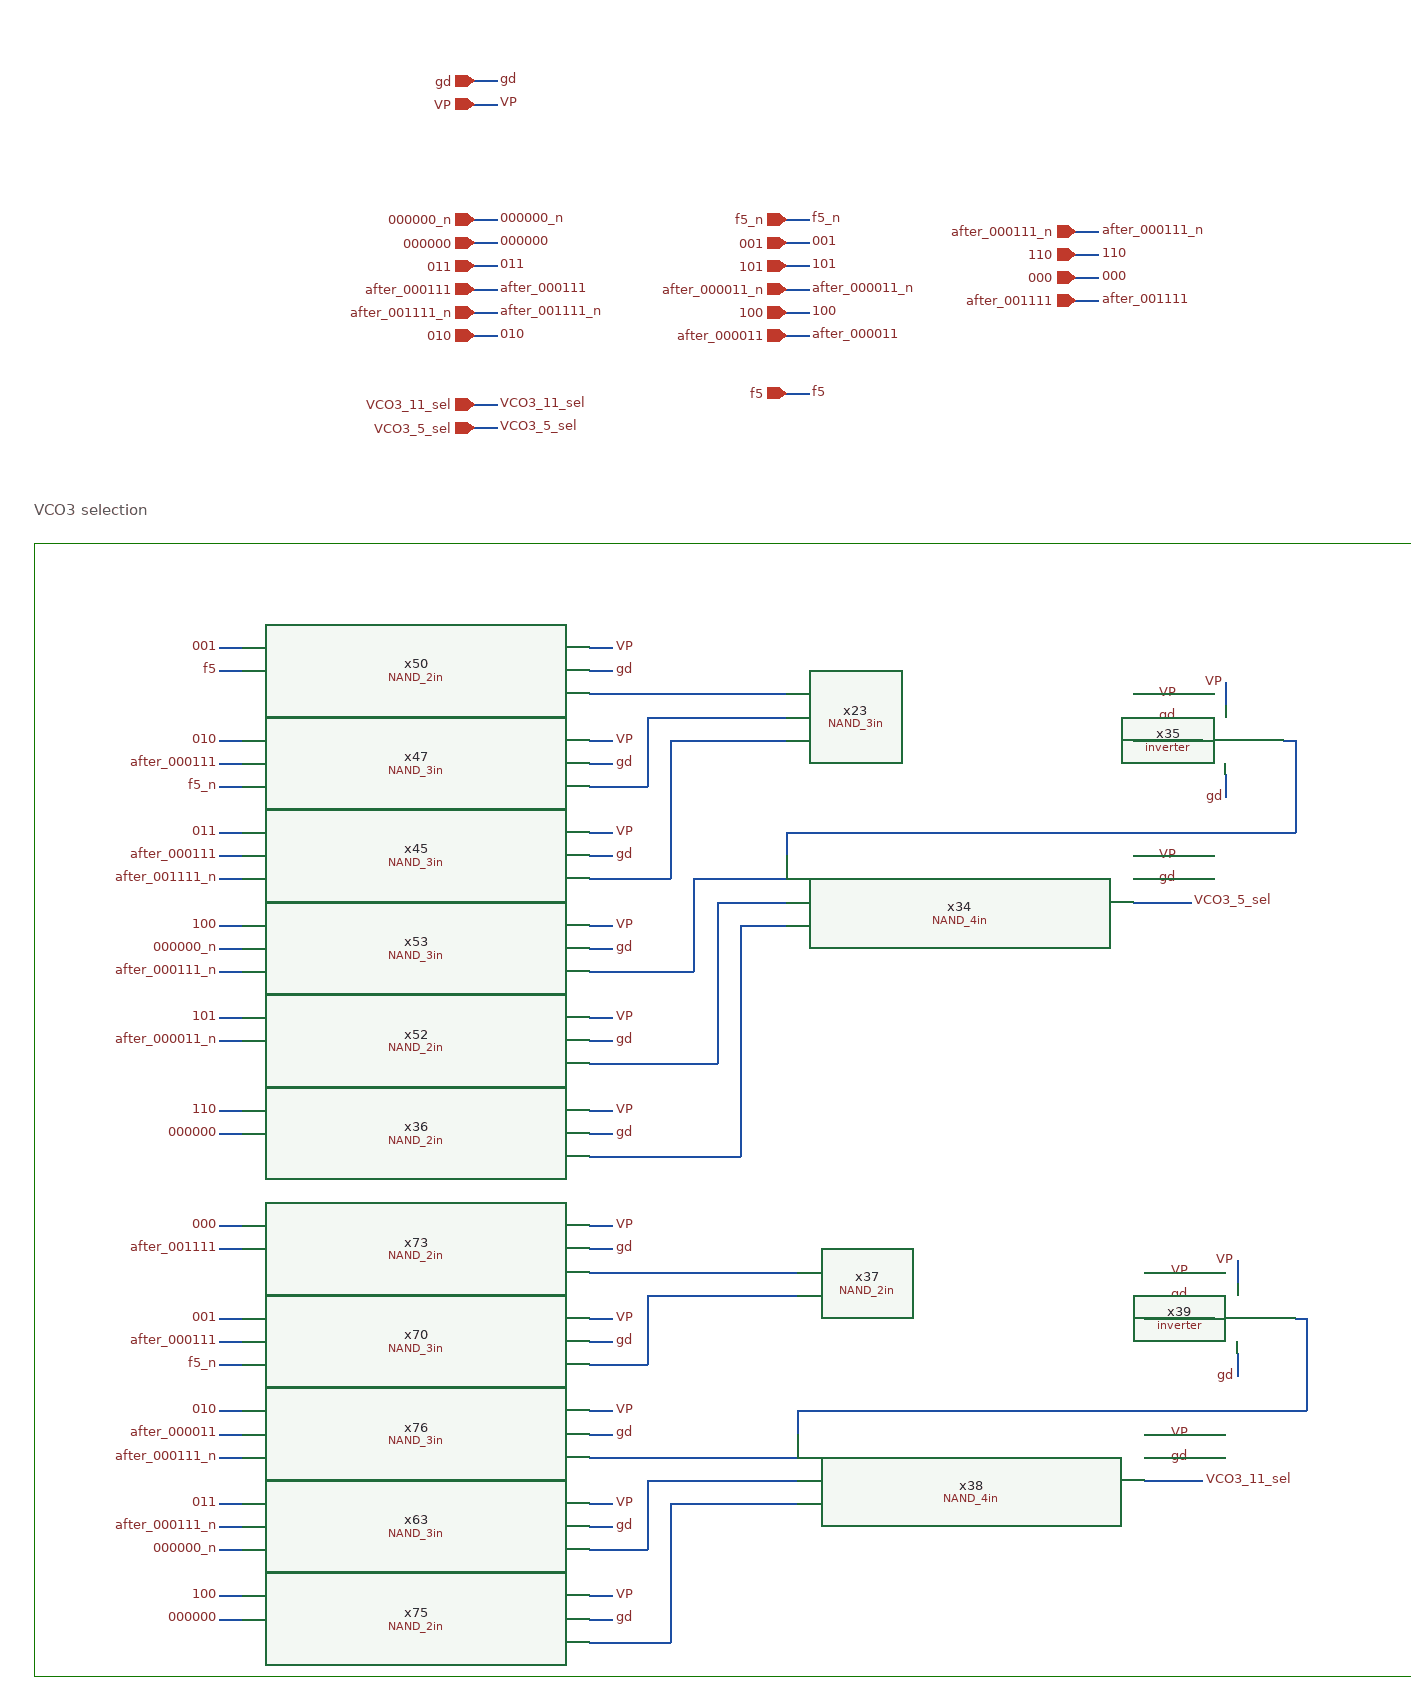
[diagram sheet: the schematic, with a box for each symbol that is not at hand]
v {xschem version=3.4.8RC file_version=1.3}
G {}
K {}
V {}
S {}
F {}
E {}
L 4 1290 -1980 1290 -1640 {}
L 4 1290 -2320 1290 -1980 {}
L 4 1290 -2520 1290 -2180 {}
L 4 1290 -2050 1290 -1710 {}
L 4 2850 -2270 2850 -1930 {}
L 4 2850 -2520 2850 -2180 {}
L 4 2850 -2050 2850 -1710 {}
L 4 1290 -2520 1630 -2520 {}
L 4 1630 -2520 1970 -2520 {}
L 4 1960 -2520 2300 -2520 {}
L 4 2180 -2520 2520 -2520 {}
L 4 1620 -2520 1960 -2520 {}
L 4 1960 -2520 2300 -2520 {}
L 4 2290 -2520 2630 -2520 {}
L 4 2510 -2520 2850 -2520 {}
L 4 1290 -1540 1630 -1540 {}
L 4 1620 -1540 1960 -1540 {}
L 4 1960 -1540 2300 -1540 {}
L 4 2290 -1540 2630 -1540 {}
L 4 2510 -1540 2850 -1540 {}
L 4 1290 -1880 1290 -1540 {}
L 4 2850 -1880 2850 -1540 {}
T {VCO3 selection} 1290 -2560 0 0 0.4 0.4 {}
N 1670 -2920 1690 -2920 {lab=gd}
N 1670 -2900 1690 -2900 {lab=VP}
N 1670 -2800 1690 -2800 {lab=000000_n}
N 1670 -2780 1690 -2780 {lab=000000}
N 1670 -2640 1690 -2640 {lab=VCO3_11_sel}
N 1670 -2620 1690 -2620 {lab=VCO3_5_sel}
N 1670 -2760 1690 -2760 {lab=011}
N 1670 -2740 1690 -2740 {lab=after_000111}
N 1670 -2720 1690 -2720 {lab=after_001111_n}
N 1670 -2700 1690 -2700 {lab=010}
N 1940 -2780 1960 -2780 {lab=001}
N 1940 -2760 1960 -2760 {lab=101}
N 1940 -2800 1960 -2800 {lab=f5_n}
N 1940 -2720 1960 -2720 {lab=100}
N 1940 -2700 1960 -2700 {lab=after_000011}
N 1940 -2740 1960 -2740 {lab=after_000011_n}
N 2190 -2770 2210 -2770 {lab=110}
N 2190 -2750 2210 -2750 {lab=000}
N 2190 -2790 2210 -2790 {lab=after_000111_n}
N 2190 -2730 2210 -2730 {lab=after_001111}
N 1940 -2650 1960 -2650 {lab=f5}
N 1770 -2250 1790 -2250 {lab=gd}
N 1770 -2270 1790 -2270 {lab=VP}
N 1770 -2230 1840 -2230 {lab=#net1}
N 1450 -2270 1470 -2270 {lab=011}
N 1450 -2230 1470 -2230 {lab=after_001111_n}
N 1450 -2250 1470 -2250 {lab=after_000111}
N 1770 -2330 1790 -2330 {lab=gd}
N 1770 -2350 1790 -2350 {lab=VP}
N 1770 -2310 1820 -2310 {lab=#net2}
N 1450 -2350 1470 -2350 {lab=010}
N 1450 -2310 1470 -2310 {lab=f5_n}
N 1450 -2330 1470 -2330 {lab=after_000111}
N 1770 -2410 1790 -2410 {lab=gd}
N 1770 -2430 1790 -2430 {lab=VP}
N 1770 -2390 1940 -2390 {lab=#net3}
N 1450 -2430 1470 -2430 {lab=001}
N 1450 -2410 1470 -2410 {lab=f5}
N 1770 -2090 1790 -2090 {lab=gd}
N 1770 -2110 1790 -2110 {lab=VP}
N 1450 -2110 1470 -2110 {lab=101}
N 1450 -2090 1470 -2090 {lab=after_000011_n}
N 1770 -2170 1790 -2170 {lab=gd}
N 1770 -2190 1790 -2190 {lab=VP}
N 1770 -2150 1860 -2150 {lab=#net4}
N 1450 -2190 1470 -2190 {lab=100}
N 1450 -2150 1470 -2150 {lab=after_000111_n}
N 1450 -2170 1470 -2170 {lab=000000_n}
N 1770 -2010 1790 -2010 {lab=gd}
N 1770 -2030 1790 -2030 {lab=VP}
N 1770 -1990 1900 -1990 {lab=#net5}
N 1450 -2030 1470 -2030 {lab=110}
N 1450 -2010 1470 -2010 {lab=000000}
N 1770 -1670 1790 -1670 {lab=gd}
N 1770 -1690 1790 -1690 {lab=VP}
N 1770 -1650 1820 -1650 {lab=#net6}
N 1450 -1690 1470 -1690 {lab=011}
N 1450 -1670 1470 -1670 {lab=after_000111_n}
N 1770 -1830 1790 -1830 {lab=gd}
N 1770 -1850 1790 -1850 {lab=VP}
N 1770 -1810 1820 -1810 {lab=#net7}
N 1450 -1850 1470 -1850 {lab=001}
N 1450 -1810 1470 -1810 {lab=f5_n}
N 1450 -1830 1470 -1830 {lab=after_000111}
N 1770 -1910 1790 -1910 {lab=gd}
N 1770 -1930 1790 -1930 {lab=VP}
N 1770 -1890 1950 -1890 {lab=#net8}
N 1450 -1930 1470 -1930 {lab=000}
N 1450 -1910 1470 -1910 {lab=after_001111}
N 1770 -1590 1790 -1590 {lab=gd}
N 1770 -1610 1790 -1610 {lab=VP}
N 1770 -1570 1840 -1570 {lab=#net9}
N 1450 -1610 1470 -1610 {lab=100}
N 1450 -1590 1470 -1590 {lab=000000}
N 1770 -1750 1790 -1750 {lab=gd}
N 1770 -1770 1790 -1770 {lab=VP}
N 1770 -1730 1950 -1730 {lab=#net10}
N 1450 -1770 1470 -1770 {lab=010}
N 1450 -1730 1470 -1730 {lab=after_000111_n}
N 1450 -1750 1470 -1750 {lab=after_000011}
N 2240 -2370 2260 -2370 {lab=gd}
N 2240 -2390 2260 -2390 {lab=VP}
N 2240 -2350 2300 -2350 {lab=#net11}
N 2240 -2230 2260 -2230 {lab=gd}
N 2240 -2250 2260 -2250 {lab=VP}
N 2240 -2210 2290 -2210 {lab=VCO3_5_sel}
N 2320 -2320 2320 -2300 {lab=gd}
N 2320 -2400 2320 -2380 {lab=VP}
N 2370 -2350 2380 -2350 {lab=#net12}
N 2380 -2350 2380 -2270 {lab=#net12}
N 1940 -2270 2380 -2270 {lab=#net12}
N 1940 -2270 1940 -2250 {lab=#net12}
N 1820 -2370 1820 -2310 {lab=#net2}
N 1820 -2370 1940 -2370 {lab=#net2}
N 1840 -2350 1940 -2350 {lab=#net1}
N 1840 -2350 1840 -2230 {lab=#net1}
N 1860 -2230 1860 -2150 {lab=#net4}
N 1860 -2230 1940 -2230 {lab=#net4}
N 1880 -2210 1940 -2210 {lab=#net13}
N 1880 -2210 1880 -2070 {lab=#net13}
N 1770 -2070 1880 -2070 {lab=#net13}
N 1900 -2190 1900 -1990 {lab=#net5}
N 1900 -2190 1940 -2190 {lab=#net5}
N 2250 -1870 2270 -1870 {lab=gd}
N 2250 -1890 2270 -1890 {lab=VP}
N 2250 -1850 2310 -1850 {lab=#net14}
N 2250 -1730 2270 -1730 {lab=gd}
N 2250 -1750 2270 -1750 {lab=VP}
N 2250 -1710 2300 -1710 {lab=VCO3_11_sel}
N 2330 -1820 2330 -1800 {lab=gd}
N 2330 -1900 2330 -1880 {lab=VP}
N 2380 -1850 2390 -1850 {lab=#net15}
N 2390 -1850 2390 -1770 {lab=#net15}
N 1950 -1770 2390 -1770 {lab=#net15}
N 1950 -1770 1950 -1750 {lab=#net15}
N 1820 -1870 1820 -1810 {lab=#net7}
N 1820 -1870 1950 -1870 {lab=#net7}
N 1820 -1710 1820 -1650 {lab=#net6}
N 1820 -1710 1950 -1710 {lab=#net6}
N 1840 -1690 1840 -1570 {lab=#net9}
N 1840 -1690 1950 -1690 {lab=#net9}
N 1450 -1650 1470 -1650 {lab=000000_n}
C {iopin.sym} 1670 -2920 2 0 {name=p46 lab=gd}
C {lab_wire.sym} 1690 -2920 2 0 {name=p53 sig_type=std_logic lab=gd}
C {iopin.sym} 1670 -2900 2 0 {name=p54 lab=VP}
C {ipin.sym} 1670 -2800 0 0 {name=p59 lab=000000_n}
C {lab_wire.sym} 1690 -2800 2 0 {name=p60 sig_type=std_logic lab=000000_n}
C {ipin.sym} 1670 -2780 0 0 {name=p61 lab=000000}
C {lab_wire.sym} 1690 -2780 2 0 {name=p63 sig_type=std_logic lab=000000}
C {lab_wire.sym} 1690 -2900 2 0 {name=p1 sig_type=std_logic lab=VP}
C {opin.sym} 1670 -2640 0 1 {name=p6 lab=VCO3_11_sel}
C {lab_wire.sym} 1690 -2640 2 0 {name=p7 sig_type=std_logic lab=VCO3_11_sel}
C {opin.sym} 1670 -2620 0 1 {name=p8 lab=VCO3_5_sel}
C {lab_wire.sym} 1690 -2620 2 0 {name=p9 sig_type=std_logic lab=VCO3_5_sel}
C {ipin.sym} 1670 -2760 0 0 {name=p19 lab=011}
C {lab_wire.sym} 1690 -2760 2 0 {name=p22 sig_type=std_logic lab=011}
C {ipin.sym} 1670 -2740 0 0 {name=p23 lab=after_000111}
C {lab_wire.sym} 1690 -2740 2 0 {name=p24 sig_type=std_logic lab=after_000111}
C {ipin.sym} 1670 -2720 0 0 {name=p25 lab=after_001111_n}
C {lab_wire.sym} 1690 -2720 2 0 {name=p26 sig_type=std_logic lab=after_001111_n}
C {ipin.sym} 1670 -2700 0 0 {name=p27 lab=010}
C {lab_wire.sym} 1690 -2700 2 0 {name=p28 sig_type=std_logic lab=010}
C {ipin.sym} 1940 -2780 0 0 {name=p3 lab=001}
C {lab_wire.sym} 1960 -2780 2 0 {name=p4 sig_type=std_logic lab=001}
C {ipin.sym} 1940 -2760 0 0 {name=p5 lab=101}
C {lab_wire.sym} 1960 -2760 2 0 {name=p10 sig_type=std_logic lab=101}
C {ipin.sym} 1940 -2800 0 0 {name=p11 lab=f5_n}
C {lab_wire.sym} 1960 -2800 2 0 {name=p12 sig_type=std_logic lab=f5_n}
C {ipin.sym} 1940 -2720 0 0 {name=p13 lab=100}
C {lab_wire.sym} 1960 -2720 2 0 {name=p14 sig_type=std_logic lab=100}
C {ipin.sym} 1940 -2700 0 0 {name=p15 lab=after_000011}
C {lab_wire.sym} 1960 -2700 2 0 {name=p16 sig_type=std_logic lab=after_000011}
C {ipin.sym} 1940 -2740 0 0 {name=p17 lab=after_000011_n}
C {lab_wire.sym} 1960 -2740 2 0 {name=p18 sig_type=std_logic lab=after_000011_n}
C {ipin.sym} 2190 -2770 0 0 {name=p29 lab=110}
C {lab_wire.sym} 2210 -2770 2 0 {name=p30 sig_type=std_logic lab=110}
C {ipin.sym} 2190 -2750 0 0 {name=p31 lab=000}
C {lab_wire.sym} 2210 -2750 2 0 {name=p32 sig_type=std_logic lab=000}
C {ipin.sym} 2190 -2790 0 0 {name=p33 lab=after_000111_n}
C {lab_wire.sym} 2210 -2790 2 0 {name=p34 sig_type=std_logic lab=after_000111_n}
C {ipin.sym} 2190 -2730 0 0 {name=p39 lab=after_001111}
C {lab_wire.sym} 2210 -2730 2 0 {name=p40 sig_type=std_logic lab=after_001111}
C {ipin.sym} 1940 -2650 0 0 {name=p2 lab=f5}
C {lab_wire.sym} 1960 -2650 2 0 {name=p20 sig_type=std_logic lab=f5}
C {NAND_3in.sym} 1620 -2250 0 0 {name=x45}
C {lab_wire.sym} 1790 -2270 2 0 {name=p221 sig_type=std_logic lab=VP}
C {lab_wire.sym} 1790 -2250 2 0 {name=p222 sig_type=std_logic lab=gd}
C {NAND_3in.sym} 1620 -2330 0 0 {name=x47}
C {lab_wire.sym} 1790 -2350 2 0 {name=p225 sig_type=std_logic lab=VP}
C {lab_wire.sym} 1790 -2330 2 0 {name=p226 sig_type=std_logic lab=gd}
C {lab_wire.sym} 1790 -2430 2 0 {name=p229 sig_type=std_logic lab=VP}
C {lab_wire.sym} 1790 -2410 2 0 {name=p230 sig_type=std_logic lab=gd}
C {NAND_2in.sym} 1620 -2410 0 0 {name=x50}
C {lab_wire.sym} 1790 -2110 2 0 {name=p233 sig_type=std_logic lab=VP}
C {lab_wire.sym} 1790 -2090 2 0 {name=p234 sig_type=std_logic lab=gd}
C {NAND_2in.sym} 1620 -2090 0 0 {name=x52}
C {NAND_3in.sym} 1620 -2170 0 0 {name=x53}
C {lab_wire.sym} 1790 -2190 2 0 {name=p237 sig_type=std_logic lab=VP}
C {lab_wire.sym} 1790 -2170 2 0 {name=p238 sig_type=std_logic lab=gd}
C {lab_wire.sym} 1790 -2030 2 0 {name=p241 sig_type=std_logic lab=VP}
C {lab_wire.sym} 1790 -2010 2 0 {name=p242 sig_type=std_logic lab=gd}
C {lab_wire.sym} 1450 -2270 0 0 {name=p253 sig_type=std_logic lab=011}
C {lab_wire.sym} 1450 -2350 0 0 {name=p254 sig_type=std_logic lab=010}
C {lab_wire.sym} 1450 -2110 0 0 {name=p256 sig_type=std_logic lab=101}
C {lab_wire.sym} 1450 -2030 0 0 {name=p257 sig_type=std_logic lab=110}
C {lab_wire.sym} 1450 -2190 0 0 {name=p258 sig_type=std_logic lab=100}
C {lab_wire.sym} 1450 -2250 0 0 {name=p263 sig_type=std_logic lab=after_000111}
C {lab_wire.sym} 1450 -2230 0 0 {name=p264 sig_type=std_logic lab=after_001111_n}
C {lab_wire.sym} 1450 -2330 0 0 {name=p265 sig_type=std_logic lab=after_000111}
C {lab_wire.sym} 1450 -2310 0 0 {name=p266 sig_type=std_logic lab=f5_n}
C {lab_wire.sym} 1450 -2410 0 0 {name=p267 sig_type=std_logic lab=f5}
C {lab_wire.sym} 1450 -2090 0 0 {name=p268 sig_type=std_logic lab=after_000011_n}
C {lab_wire.sym} 1450 -2150 0 0 {name=p270 sig_type=std_logic lab=after_000111_n}
C {NAND_3in.sym} 1620 -1670 0 0 {name=x63}
C {lab_wire.sym} 1790 -1690 2 0 {name=p275 sig_type=std_logic lab=VP}
C {lab_wire.sym} 1790 -1670 2 0 {name=p276 sig_type=std_logic lab=gd}
C {NAND_3in.sym} 1620 -1830 0 0 {name=x70}
C {lab_wire.sym} 1790 -1850 2 0 {name=p289 sig_type=std_logic lab=VP}
C {lab_wire.sym} 1790 -1830 2 0 {name=p290 sig_type=std_logic lab=gd}
C {lab_wire.sym} 1790 -1930 2 0 {name=p293 sig_type=std_logic lab=VP}
C {lab_wire.sym} 1790 -1910 2 0 {name=p294 sig_type=std_logic lab=gd}
C {NAND_2in.sym} 1620 -1910 0 0 {name=x73}
C {lab_wire.sym} 1790 -1610 2 0 {name=p297 sig_type=std_logic lab=VP}
C {lab_wire.sym} 1790 -1590 2 0 {name=p298 sig_type=std_logic lab=gd}
C {NAND_2in.sym} 1620 -1590 0 0 {name=x75}
C {NAND_3in.sym} 1620 -1750 0 0 {name=x76}
C {lab_wire.sym} 1790 -1770 2 0 {name=p301 sig_type=std_logic lab=VP}
C {lab_wire.sym} 1790 -1750 2 0 {name=p302 sig_type=std_logic lab=gd}
C {lab_wire.sym} 1450 -1850 0 0 {name=p307 sig_type=std_logic lab=001}
C {lab_wire.sym} 1450 -1930 0 0 {name=p308 sig_type=std_logic lab=000}
C {lab_wire.sym} 1450 -1610 0 0 {name=p311 sig_type=std_logic lab=100}
C {lab_wire.sym} 1450 -1770 0 0 {name=p312 sig_type=std_logic lab=010}
C {lab_wire.sym} 1450 -1690 0 0 {name=p313 sig_type=std_logic lab=011}
C {lab_wire.sym} 1450 -1830 0 0 {name=p315 sig_type=std_logic lab=after_000111}
C {lab_wire.sym} 1450 -1810 0 0 {name=p316 sig_type=std_logic lab=f5_n}
C {lab_wire.sym} 1450 -1910 0 0 {name=p317 sig_type=std_logic lab=after_001111}
C {lab_wire.sym} 1450 -1750 0 0 {name=p319 sig_type=std_logic lab=after_000011}
C {lab_wire.sym} 1450 -1730 0 0 {name=p320 sig_type=std_logic lab=after_000111_n}
C {lab_wire.sym} 1450 -2430 0 0 {name=p55 sig_type=std_logic lab=001}
C {lab_wire.sym} 2290 -2210 2 0 {name=p153 sig_type=std_logic lab=VCO3_5_sel}
C {NAND_3in.sym} 2090 -2370 0 0 {name=x23}
C {lab_wire.sym} 2260 -2390 2 0 {name=p154 sig_type=std_logic lab=VP}
C {lab_wire.sym} 2260 -2370 2 0 {name=p155 sig_type=std_logic lab=gd}
C {NAND_4in.sym} 2090 -2220 0 0 {name=x34}
C {lab_wire.sym} 2260 -2250 2 0 {name=p156 sig_type=std_logic lab=VP}
C {lab_wire.sym} 2260 -2230 2 0 {name=p163 sig_type=std_logic lab=gd}
C {inverter.sym} 2320 -2350 0 0 {name=x35}
C {lab_wire.sym} 2320 -2300 3 0 {name=p165 sig_type=std_logic lab=gd}
C {lab_wire.sym} 2320 -2400 1 0 {name=p166 sig_type=std_logic lab=VP}
C {lab_wire.sym} 1450 -2170 0 0 {name=p164 sig_type=std_logic lab=000000_n}
C {lab_wire.sym} 1450 -2010 0 0 {name=p169 sig_type=std_logic lab=000000}
C {NAND_2in.sym} 1620 -2010 0 0 {name=x36}
C {lab_wire.sym} 2270 -1890 2 0 {name=p173 sig_type=std_logic lab=VP}
C {lab_wire.sym} 2270 -1870 2 0 {name=p174 sig_type=std_logic lab=gd}
C {NAND_4in.sym} 2100 -1720 0 0 {name=x38}
C {lab_wire.sym} 2270 -1750 2 0 {name=p177 sig_type=std_logic lab=VP}
C {lab_wire.sym} 2270 -1730 2 0 {name=p178 sig_type=std_logic lab=gd}
C {inverter.sym} 2330 -1850 0 0 {name=x39}
C {lab_wire.sym} 2330 -1800 3 0 {name=p179 sig_type=std_logic lab=gd}
C {lab_wire.sym} 2330 -1900 1 0 {name=p180 sig_type=std_logic lab=VP}
C {NAND_2in.sym} 2100 -1870 0 0 {name=x37}
C {lab_wire.sym} 2300 -1710 2 0 {name=p170 sig_type=std_logic lab=VCO3_11_sel}
C {lab_wire.sym} 1450 -1670 0 0 {name=p181 sig_type=std_logic lab=after_000111_n}
C {lab_wire.sym} 1450 -1650 0 0 {name=p182 sig_type=std_logic lab=000000_n}
C {lab_wire.sym} 1450 -1590 0 0 {name=p183 sig_type=std_logic lab=000000}
